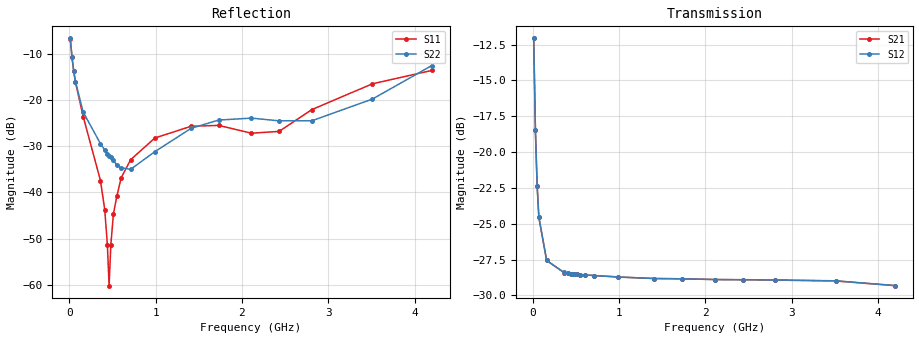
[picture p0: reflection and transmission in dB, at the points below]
! Integrated Device Technology
! Corporate Headquarters
! 6024 Silver Creek Valley Road
! San Jose, CA 95138  USA
! Phone:  1-408-284-8200
! Toll Free:  1-800-223-1366
! Webpage:  http://www.idt.com/
! Timing and RF Division
! 515 Groton Road, Suite 102
! Westford, MA 01886-6024
! Device:  F1950
! Description: 7-bit 0.25 dB Digital Step Attenuator
! Frequency:  150.0 -  4000.00 MHz
! Package:  4x4 mm Thin QFN Plastic Package: 24 pin
! Ports:  2 RF, 12 DC
!  Pin  1  = D0
!  Pin  2  = VDD
!  Pin  3  = Vmode
!  Pin  4  = GND
!  Pin  5  = RF1  =  Port 1
!  Pin  6  = GND
!  Pin  7  = GND
!  Pin  8  = GND
!  Pin  9  = GND
!  Pin 10  = GND
!  Pin 11  = GND
!  Pin 12  = GND
!  Pin 13  = GND
!  Pin 14  = RF2  =  Port 2
!  Pin 15  = GND
!  Pin 16  = LE
!  Pin 17  = CLK
!  Pin 18  = DATE
!  Pin 19  = D6
!  Pin 20  = D5
!  Pin 21  = D4
!  Pin 22  = D3
!  Pin 23  = D2
!  Pin 24  = D1
! State:  111
! Atten State:  27.75 dB
! Voltage:  +5.00 Volts
! Current:  Not Measured mA
! Data:  The device was measured on a the F195X evaluation board which has
!  individual transmission lines to the RF pins.  Data was collected
!  using a calibrated network analyzer.  The evaluation board was
!  de-embedded using a TRL calibration technique.
!  The reference plane is the edge of the package pin.
! Misc:  Board 2019
!  Action Tracker AT0250
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# GHz S dB R 50
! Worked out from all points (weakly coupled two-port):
!   420 points, 10 MHz to 4.2 GHz, reference 50 ohm
!   highest |S21| = -12.06 dB at 10 MHz (marker M1); lowest = -29.3 dB at 4.2 GHz (marker M2)
!   lowest |S11| = -60.2 dB at 460 MHz (marker M3), VSWR 1.00, Z = 49.9 - j0.0433 ohm
!   |S11| at or under -10 dB: 26.23 MHz to end of sweep
!   |S22| runs from -35.3 to -6.6 dB; largest |S21 - S12| = 8.2e-05
!   S11 on the Smith chart (normalised r, x): 10 MHz: 1.97, -1.10; 30 MHz: 1.29, -0.63; 70 MHz: 1.09, -0.32; 460 MHz: 1.00, -0.00; 4.2 GHz: 0.69, +0.17
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0.01  -6.68 -28.2  -12.06 -39.4  -12.06 -39.4  -6.60 -29.0
0.03  -10.69 -49.9  -18.48 -56.5  -18.48 -56.5  -10.62 -51.4
0.05  -13.76 -59.8  -22.35 -54.1  -22.35 -54.1  -13.58 -61.6
0.07  -16.13 -65.5  -24.55 -47.7  -24.55 -47.7  -15.97 -66.7
0.16  -23.57 -71.6  -27.56 -27.8  -27.56 -27.8  -22.60 -75.3
0.36  -37.43 -67.0  -28.40 -16.2  -28.39 -16.2  -29.43 -85.1
0.41  -43.86 -72.2  -28.45 -15.2  -28.45 -15.3  -30.84 -87.2
0.44  -51.39 -85.0  -28.48 -14.8  -28.48 -14.8  -31.67 -91.2
0.46  -60.22 -153.6  -28.50 -14.6  -28.49 -14.6  -32.09 -94.5
0.48  -51.37 141.5  -28.51 -14.4  -28.51 -14.4  -32.40 -97.4
0.51  -44.68 135.3  -28.53 -14.2  -28.53 -14.2  -32.94 -100.2
0.55  -40.80 133.1  -28.55 -14.0  -28.55 -14.0  -34.12 -105.6
0.6  -36.83 133.6  -28.57 -13.8  -28.57 -13.8  -34.65 -117.6
0.71  -32.90 136.3  -28.61 -13.8  -28.61 -13.8  -34.99 -139.2
0.99  -28.20 146.3  -28.71 -14.8  -28.72 -14.8  -31.16 179.5
1.41  -25.66 162.1  -28.82 -17.2  -28.82 -17.2  -26.11 160.0
1.73  -25.47 167.4  -28.84 -19.3  -28.84 -19.4  -24.31 151.6
2.11  -27.16 156.5  -28.89 -22.6  -28.89 -22.7  -23.89 141.6
2.43  -26.77 124.5  -28.91 -24.9  -28.90 -24.9  -24.48 130.8
2.81  -22.04 104.2  -28.93 -28.4  -28.92 -28.5  -24.46 115.3
3.51  -16.46 116.7  -28.99 -34.3  -28.98 -34.4  -19.77 112.8
4.2  -13.55 145.2  -29.32 -37.8  -29.31 -37.9  -12.49 127.0
